VERSION 5.7 ;
BUSBITCHARS "[]" ;
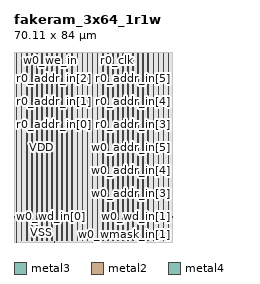
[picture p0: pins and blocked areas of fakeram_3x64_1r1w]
MACRO fakeram_3x64_1r1w
  FOREIGN fakeram_3x64_1r1w 0 0 ;
  SYMMETRY X Y R90 ;
  SIZE 70.110 BY 84.000 ;
  CLASS BLOCK ;
  PIN w0_wmask_in[0]
    DIRECTION INPUT ;
    USE SIGNAL ;
    SHAPE ABUTMENT ;
    PORT
      LAYER metal3 ;
      RECT 0.000 0.805 0.210 0.875 ;
    END
  END w0_wmask_in[0]
  PIN w0_wmask_in[1]
    DIRECTION INPUT ;
    USE SIGNAL ;
    SHAPE ABUTMENT ;
    PORT
      LAYER metal3 ;
      RECT 69.900 0.805 70.110 0.875 ;
    END
  END w0_wmask_in[1]
  PIN w0_wmask_in[2]
    DIRECTION INPUT ;
    USE SIGNAL ;
    SHAPE ABUTMENT ;
    PORT
      LAYER metal2 ;
      RECT 1.105 83.790 1.175 84.000 ;
    END
  END w0_wmask_in[2]
  PIN w0_wd_in[0]
    DIRECTION INPUT ;
    USE SIGNAL ;
    SHAPE ABUTMENT ;
    PORT
      LAYER metal3 ;
      RECT 0.000 11.025 0.210 11.095 ;
    END
  END w0_wd_in[0]
  PIN w0_wd_in[1]
    DIRECTION INPUT ;
    USE SIGNAL ;
    SHAPE ABUTMENT ;
    PORT
      LAYER metal3 ;
      RECT 69.900 11.025 70.110 11.095 ;
    END
  END w0_wd_in[1]
  PIN w0_wd_in[2]
    DIRECTION OUTPUT ;
    USE SIGNAL ;
    SHAPE ABUTMENT ;
    PORT
      LAYER metal2 ;
      RECT 1.105 0.000 1.175 0.210 ;
    END
  END w0_wd_in[2]
  PIN r0_rd_out[0]
    DIRECTION OUTPUT ;
    USE SIGNAL ;
    SHAPE ABUTMENT ;
    PORT
      LAYER metal2 ;
      RECT 18.015 0.000 18.085 0.210 ;
    END
  END r0_rd_out[0]
  PIN r0_rd_out[1]
    DIRECTION OUTPUT ;
    USE SIGNAL ;
    SHAPE ABUTMENT ;
    PORT
      LAYER metal2 ;
      RECT 34.925 0.000 34.995 0.210 ;
    END
  END r0_rd_out[1]
  PIN r0_rd_out[2]
    DIRECTION OUTPUT ;
    USE SIGNAL ;
    SHAPE ABUTMENT ;
    PORT
      LAYER metal2 ;
      RECT 8.515 83.790 8.585 84.000 ;
    END
  END r0_rd_out[2]
  PIN w0_addr_in[0]
    DIRECTION INPUT ;
    USE SIGNAL ;
    SHAPE ABUTMENT ;
    PORT
      LAYER metal3 ;
      RECT 0.000 21.245 0.210 21.315 ;
    END
  END w0_addr_in[0]
  PIN w0_addr_in[1]
    DIRECTION INPUT ;
    USE SIGNAL ;
    SHAPE ABUTMENT ;
    PORT
      LAYER metal3 ;
      RECT 0.000 31.465 0.210 31.535 ;
    END
  END w0_addr_in[1]
  PIN w0_addr_in[2]
    DIRECTION INPUT ;
    USE SIGNAL ;
    SHAPE ABUTMENT ;
    PORT
      LAYER metal3 ;
      RECT 0.000 41.685 0.210 41.755 ;
    END
  END w0_addr_in[2]
  PIN w0_addr_in[3]
    DIRECTION INPUT ;
    USE SIGNAL ;
    SHAPE ABUTMENT ;
    PORT
      LAYER metal3 ;
      RECT 69.900 21.245 70.110 21.315 ;
    END
  END w0_addr_in[3]
  PIN w0_addr_in[4]
    DIRECTION INPUT ;
    USE SIGNAL ;
    SHAPE ABUTMENT ;
    PORT
      LAYER metal3 ;
      RECT 69.900 31.465 70.110 31.535 ;
    END
  END w0_addr_in[4]
  PIN w0_addr_in[5]
    DIRECTION INPUT ;
    USE SIGNAL ;
    SHAPE ABUTMENT ;
    PORT
      LAYER metal3 ;
      RECT 69.900 41.685 70.110 41.755 ;
    END
  END w0_addr_in[5]
  PIN r0_addr_in[0]
    DIRECTION INPUT ;
    USE SIGNAL ;
    SHAPE ABUTMENT ;
    PORT
      LAYER metal3 ;
      RECT 0.000 51.905 0.210 51.975 ;
    END
  END r0_addr_in[0]
  PIN r0_addr_in[1]
    DIRECTION INPUT ;
    USE SIGNAL ;
    SHAPE ABUTMENT ;
    PORT
      LAYER metal3 ;
      RECT 0.000 62.125 0.210 62.195 ;
    END
  END r0_addr_in[1]
  PIN r0_addr_in[2]
    DIRECTION INPUT ;
    USE SIGNAL ;
    SHAPE ABUTMENT ;
    PORT
      LAYER metal3 ;
      RECT 0.000 72.345 0.210 72.415 ;
    END
  END r0_addr_in[2]
  PIN r0_addr_in[3]
    DIRECTION INPUT ;
    USE SIGNAL ;
    SHAPE ABUTMENT ;
    PORT
      LAYER metal3 ;
      RECT 69.900 51.905 70.110 51.975 ;
    END
  END r0_addr_in[3]
  PIN r0_addr_in[4]
    DIRECTION INPUT ;
    USE SIGNAL ;
    SHAPE ABUTMENT ;
    PORT
      LAYER metal3 ;
      RECT 69.900 62.125 70.110 62.195 ;
    END
  END r0_addr_in[4]
  PIN r0_addr_in[5]
    DIRECTION INPUT ;
    USE SIGNAL ;
    SHAPE ABUTMENT ;
    PORT
      LAYER metal3 ;
      RECT 69.900 72.345 70.110 72.415 ;
    END
  END r0_addr_in[5]
  PIN w0_we_in
    DIRECTION INPUT ;
    USE SIGNAL ;
    SHAPE ABUTMENT ;
    PORT
      LAYER metal2 ;
      RECT 15.925 83.790 15.995 84.000 ;
    END
  END w0_we_in
  PIN w0_ce_in
    DIRECTION INPUT ;
    USE SIGNAL ;
    SHAPE ABUTMENT ;
    PORT
      LAYER metal2 ;
      RECT 23.335 83.790 23.405 84.000 ;
    END
  END w0_ce_in
  PIN w0_clk
    DIRECTION INPUT ;
    USE SIGNAL ;
    SHAPE ABUTMENT ;
    PORT
      LAYER metal2 ;
      RECT 30.745 83.790 30.815 84.000 ;
    END
  END w0_clk
  PIN r0_ce_in
    DIRECTION INPUT ;
    USE SIGNAL ;
    SHAPE ABUTMENT ;
    PORT
      LAYER metal2 ;
      RECT 38.155 83.790 38.225 84.000 ;
    END
  END r0_ce_in
  PIN r0_clk
    DIRECTION INPUT ;
    USE SIGNAL ;
    SHAPE ABUTMENT ;
    PORT
      LAYER metal2 ;
      RECT 45.565 83.790 45.635 84.000 ;
    END
  END r0_clk
  PIN VSS
    DIRECTION INOUT ;
    USE GROUND ;
    PORT
      LAYER metal4 ;
      RECT 1.000 0.840 1.280 83.160 ;
      RECT 3.240 0.840 3.520 83.160 ;
      RECT 5.480 0.840 5.760 83.160 ;
      RECT 7.720 0.840 8.000 83.160 ;
      RECT 9.960 0.840 10.240 83.160 ;
      RECT 12.200 0.840 12.480 83.160 ;
      RECT 14.440 0.840 14.720 83.160 ;
      RECT 16.680 0.840 16.960 83.160 ;
      RECT 18.920 0.840 19.200 83.160 ;
      RECT 21.160 0.840 21.440 83.160 ;
      RECT 23.400 0.840 23.680 83.160 ;
      RECT 25.640 0.840 25.920 83.160 ;
      RECT 27.880 0.840 28.160 83.160 ;
      RECT 30.120 0.840 30.400 83.160 ;
      RECT 32.360 0.840 32.640 83.160 ;
      RECT 34.600 0.840 34.880 83.160 ;
      RECT 36.840 0.840 37.120 83.160 ;
      RECT 39.080 0.840 39.360 83.160 ;
      RECT 41.320 0.840 41.600 83.160 ;
      RECT 43.560 0.840 43.840 83.160 ;
      RECT 45.800 0.840 46.080 83.160 ;
      RECT 48.040 0.840 48.320 83.160 ;
      RECT 50.280 0.840 50.560 83.160 ;
      RECT 52.520 0.840 52.800 83.160 ;
      RECT 54.760 0.840 55.040 83.160 ;
      RECT 57.000 0.840 57.280 83.160 ;
      RECT 59.240 0.840 59.520 83.160 ;
      RECT 61.480 0.840 61.760 83.160 ;
      RECT 63.720 0.840 64.000 83.160 ;
      RECT 65.960 0.840 66.240 83.160 ;
      RECT 68.200 0.840 68.480 83.160 ;
    END
  END VSS
  PIN VDD
    DIRECTION INOUT ;
    USE POWER ;
    PORT
      LAYER metal4 ;
      RECT 1.000 0.840 1.280 83.160 ;
      RECT 3.240 0.840 3.520 83.160 ;
      RECT 5.480 0.840 5.760 83.160 ;
      RECT 7.720 0.840 8.000 83.160 ;
      RECT 9.960 0.840 10.240 83.160 ;
      RECT 12.200 0.840 12.480 83.160 ;
      RECT 14.440 0.840 14.720 83.160 ;
      RECT 16.680 0.840 16.960 83.160 ;
      RECT 18.920 0.840 19.200 83.160 ;
      RECT 21.160 0.840 21.440 83.160 ;
      RECT 23.400 0.840 23.680 83.160 ;
      RECT 25.640 0.840 25.920 83.160 ;
      RECT 27.880 0.840 28.160 83.160 ;
      RECT 30.120 0.840 30.400 83.160 ;
      RECT 32.360 0.840 32.640 83.160 ;
      RECT 34.600 0.840 34.880 83.160 ;
      RECT 36.840 0.840 37.120 83.160 ;
      RECT 39.080 0.840 39.360 83.160 ;
      RECT 41.320 0.840 41.600 83.160 ;
      RECT 43.560 0.840 43.840 83.160 ;
      RECT 45.800 0.840 46.080 83.160 ;
      RECT 48.040 0.840 48.320 83.160 ;
      RECT 50.280 0.840 50.560 83.160 ;
      RECT 52.520 0.840 52.800 83.160 ;
      RECT 54.760 0.840 55.040 83.160 ;
      RECT 57.000 0.840 57.280 83.160 ;
      RECT 59.240 0.840 59.520 83.160 ;
      RECT 61.480 0.840 61.760 83.160 ;
      RECT 63.720 0.840 64.000 83.160 ;
      RECT 65.960 0.840 66.240 83.160 ;
      RECT 68.200 0.840 68.480 83.160 ;
    END
  END VDD
  OBS
    LAYER metal1 ;
    RECT 0 0 70.110 84.000 ;
    LAYER metal2 ;
    RECT 0 0 70.110 84.000 ;
    LAYER metal3 ;
    RECT 0 0 70.110 84.000 ;
    LAYER metal4 ;
    RECT 0 0 70.110 84.000 ;
    LAYER OVERLAP ;
    RECT 0 0 70.110 84.000 ;
  END
END fakeram_3x64_1r1w

END LIBRARY
